VERSION 5.7 ;
  NOWIREEXTENSIONATPIN ON ;
  DIVIDERCHAR "/" ;
  BUSBITCHARS "[]" ;
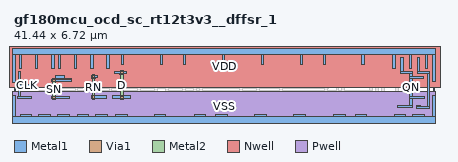
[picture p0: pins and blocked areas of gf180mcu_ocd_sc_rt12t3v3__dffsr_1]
MACRO gf180mcu_ocd_sc_rt12t3v3__dffsr_1
  CLASS CORE ;
  FOREIGN gf180mcu_ocd_sc_rt12t3v3__dffsr_1 ;
  ORIGIN 0.000 0.000 ;
  SIZE 41.440 BY 6.720 ;
  SYMMETRY X Y ;
  SITE unithd ;
  PIN D
    DIRECTION INPUT ;
    USE SIGNAL ;
    ANTENNAGATEAREA 1.672300 ;
    PORT
      LAYER Metal1 ;
        RECT 10.450 4.770 10.830 4.790 ;
        RECT 9.940 4.540 11.080 4.770 ;
        RECT 10.450 4.530 10.830 4.540 ;
        RECT 9.730 2.075 11.490 2.405 ;
      LAYER Via1 ;
        RECT 10.510 4.530 10.770 4.790 ;
        RECT 10.510 2.105 10.770 2.365 ;
      LAYER Metal2 ;
        RECT 10.500 2.045 10.780 4.855 ;
    END
  END D
  PIN CLK
    DIRECTION INPUT ;
    USE SIGNAL ;
    ANTENNAGATEAREA 1.672300 ;
    PORT
      LAYER Metal1 ;
        RECT 0.445 3.525 0.675 4.825 ;
        RECT 0.370 3.195 1.870 3.525 ;
        RECT 0.445 2.320 0.675 3.195 ;
        RECT 0.345 2.090 1.770 2.320 ;
    END
  END CLK
  PIN SN
    DIRECTION INPUT ;
    USE SIGNAL ;
    ANTENNAGATEAREA 1.672300 ;
    PORT
      LAYER Metal1 ;
        RECT 4.060 4.085 4.995 4.385 ;
        RECT 4.060 4.015 5.710 4.085 ;
        RECT 3.725 3.755 5.710 4.015 ;
        RECT 3.730 2.320 4.110 2.335 ;
        RECT 3.730 2.090 5.500 2.320 ;
        RECT 3.730 2.075 4.110 2.090 ;
      LAYER Via1 ;
        RECT 3.790 3.755 4.050 4.015 ;
        RECT 3.790 2.075 4.050 2.335 ;
      LAYER Metal2 ;
        RECT 3.780 2.010 4.060 4.075 ;
    END
  END SN
  PIN RN
    DIRECTION INPUT ;
    USE SIGNAL ;
    ANTENNAGATEAREA 1.672300 ;
    PORT
      LAYER Metal1 ;
        RECT 7.850 4.355 8.195 4.390 ;
        RECT 7.620 4.145 8.195 4.355 ;
        RECT 7.620 4.095 8.030 4.145 ;
        RECT 7.650 2.075 9.165 2.405 ;
      LAYER Via1 ;
        RECT 7.710 4.095 7.970 4.355 ;
        RECT 7.710 2.110 7.970 2.370 ;
      LAYER Metal2 ;
        RECT 7.700 2.020 7.980 4.470 ;
    END
  END RN
  PIN Q
    DIRECTION OUTPUT ;
    USE SIGNAL ;
    ANTENNADIFFAREA 0.976900 ;
    PORT
      LAYER Metal1 ;
        RECT 39.775 4.820 40.005 6.180 ;
        RECT 39.775 4.560 41.010 4.820 ;
        RECT 39.730 1.380 40.110 1.425 ;
        RECT 40.750 1.380 41.010 4.560 ;
        RECT 39.730 1.120 41.010 1.380 ;
    END
  END Q
  PIN QN
    DIRECTION OUTPUT ;
    USE SIGNAL ;
    ANTENNAGATEAREA 1.672300 ;
    ANTENNADIFFAREA 0.976900 ;
    PORT
      LAYER Metal1 ;
        RECT 38.175 4.820 38.405 6.180 ;
        RECT 38.175 4.560 39.330 4.820 ;
        RECT 39.070 4.290 39.330 4.560 ;
        RECT 39.070 4.060 40.420 4.290 ;
        RECT 39.070 2.320 39.330 4.060 ;
        RECT 39.070 2.075 40.490 2.320 ;
        RECT 39.070 1.430 39.330 2.075 ;
        RECT 38.200 1.425 39.330 1.430 ;
        RECT 37.880 1.195 39.330 1.425 ;
    END
  END QN
  PIN VDD
    DIRECTION INOUT ;
    USE POWER ;
    SHAPE ABUTMENT ;
    PORT
      LAYER Nwell ;
        RECT -0.450 3.245 42.210 7.330 ;
      LAYER Metal1 ;
        RECT -0.115 6.420 41.555 7.020 ;
        RECT -0.115 3.745 0.115 6.420 ;
        RECT 0.525 5.060 0.755 6.420 ;
        RECT 2.125 5.060 2.355 6.420 ;
        RECT 3.725 5.065 3.955 6.420 ;
        RECT 4.365 5.060 4.595 6.420 ;
        RECT 5.965 5.060 6.195 6.420 ;
        RECT 7.565 5.060 7.795 6.420 ;
        RECT 9.165 5.065 9.395 6.420 ;
        RECT 10.605 5.520 10.835 6.420 ;
        RECT 14.450 5.520 14.680 6.420 ;
        RECT 16.715 5.520 16.945 6.420 ;
        RECT 20.555 5.520 20.785 6.420 ;
        RECT 24.395 5.520 24.625 6.420 ;
        RECT 28.235 5.520 28.465 6.420 ;
        RECT 30.495 5.520 30.725 6.420 ;
        RECT 34.335 5.520 34.565 6.420 ;
        RECT 37.375 5.060 37.605 6.420 ;
        RECT 38.975 5.060 39.205 6.420 ;
        RECT 40.575 5.065 40.805 6.420 ;
        RECT 41.325 3.750 41.555 6.420 ;
    END
  END VDD
  PIN VSS
    DIRECTION INOUT ;
    USE GROUND ;
    SHAPE ABUTMENT ;
    PORT
      LAYER Pwell ;
        RECT -0.180 -0.180 41.620 2.815 ;
      LAYER Metal1 ;
        RECT -0.115 0.300 0.115 2.410 ;
        RECT 0.600 0.300 1.710 0.585 ;
        RECT 2.450 0.300 3.560 0.585 ;
        RECT 4.340 0.300 5.450 0.585 ;
        RECT 6.220 0.300 7.330 0.585 ;
        RECT 8.070 0.300 9.180 0.585 ;
        RECT 10.060 0.300 11.170 0.585 ;
        RECT 13.855 0.300 14.965 0.585 ;
        RECT 17.770 0.300 18.905 0.585 ;
        RECT 19.930 0.300 21.040 0.585 ;
        RECT 23.770 0.300 24.880 0.585 ;
        RECT 27.605 0.300 28.715 0.585 ;
        RECT 31.550 0.300 32.685 0.585 ;
        RECT 33.710 0.300 34.820 0.585 ;
        RECT 37.500 0.300 38.610 0.585 ;
        RECT 39.350 0.300 40.460 0.585 ;
        RECT 41.325 0.300 41.555 2.410 ;
        RECT -0.115 -0.300 41.555 0.300 ;
    END
  END VSS
  OBS
      LAYER Metal1 ;
        RECT 1.325 4.820 1.555 6.180 ;
        RECT 2.925 4.820 3.155 6.180 ;
        RECT 5.165 4.820 5.395 6.180 ;
        RECT 6.765 4.820 6.995 6.180 ;
        RECT 8.365 4.820 8.595 6.180 ;
        RECT 9.805 5.290 10.035 6.190 ;
        RECT 11.405 5.960 13.235 6.190 ;
        RECT 11.405 5.290 11.635 5.960 ;
        RECT 9.805 5.060 11.635 5.290 ;
        RECT 12.190 4.975 12.450 5.730 ;
        RECT 13.005 5.055 13.235 5.960 ;
        RECT 13.650 5.290 13.880 6.180 ;
        RECT 15.250 5.290 15.480 6.180 ;
        RECT 15.915 5.290 16.145 6.190 ;
        RECT 17.515 5.960 19.345 6.190 ;
        RECT 17.515 5.290 17.745 5.960 ;
        RECT 13.650 5.060 17.745 5.290 ;
        RECT 1.325 4.560 2.695 4.820 ;
        RECT 2.925 4.560 3.490 4.820 ;
        RECT 5.165 4.770 6.350 4.820 ;
        RECT 5.165 4.560 6.535 4.770 ;
        RECT 6.765 4.560 7.470 4.820 ;
        RECT 8.365 4.560 9.710 4.820 ;
        RECT 12.205 4.770 12.450 4.975 ;
        RECT 2.110 4.540 2.695 4.560 ;
        RECT 2.110 2.875 2.370 4.540 ;
        RECT 3.230 3.370 3.490 4.560 ;
        RECT 5.960 4.540 6.535 4.560 ;
        RECT 11.585 4.540 11.975 4.770 ;
        RECT 12.205 4.540 13.545 4.770 ;
        RECT 13.800 4.600 15.835 4.830 ;
        RECT 13.800 4.565 14.190 4.600 ;
        RECT 11.690 4.300 11.920 4.540 ;
        RECT 14.905 4.300 15.340 4.325 ;
        RECT 8.560 4.070 15.340 4.300 ;
        RECT 8.560 3.835 8.790 4.070 ;
        RECT 14.920 4.060 15.340 4.070 ;
        RECT 15.605 4.290 15.835 4.600 ;
        RECT 16.455 4.540 17.010 4.805 ;
        RECT 17.540 4.540 18.085 4.805 ;
        RECT 18.315 4.770 18.610 5.730 ;
        RECT 19.115 5.055 19.345 5.960 ;
        RECT 19.755 5.290 19.985 6.190 ;
        RECT 21.355 5.960 23.185 6.190 ;
        RECT 21.355 5.290 21.585 5.960 ;
        RECT 19.755 5.060 21.585 5.290 ;
        RECT 22.155 5.025 22.530 5.730 ;
        RECT 22.955 5.055 23.185 5.960 ;
        RECT 23.595 5.290 23.825 6.190 ;
        RECT 25.195 5.960 27.025 6.190 ;
        RECT 25.195 5.290 25.425 5.960 ;
        RECT 23.595 5.060 25.425 5.290 ;
        RECT 25.995 5.720 26.235 5.730 ;
        RECT 22.270 5.000 22.530 5.025 ;
        RECT 23.725 4.770 24.295 4.805 ;
        RECT 18.315 4.540 21.205 4.770 ;
        RECT 21.450 4.540 22.400 4.770 ;
        RECT 23.725 4.540 24.715 4.770 ;
        RECT 21.515 4.290 21.745 4.540 ;
        RECT 25.480 4.290 25.710 4.825 ;
        RECT 25.995 4.770 26.450 5.720 ;
        RECT 26.795 5.055 27.025 5.960 ;
        RECT 27.435 5.290 27.665 6.180 ;
        RECT 29.035 5.290 29.265 6.180 ;
        RECT 29.695 5.290 29.925 6.190 ;
        RECT 31.295 5.960 33.125 6.190 ;
        RECT 31.295 5.290 31.525 5.960 ;
        RECT 27.435 5.060 31.525 5.290 ;
        RECT 32.040 5.040 32.610 5.730 ;
        RECT 32.895 5.055 33.125 5.960 ;
        RECT 33.535 5.290 33.765 6.190 ;
        RECT 35.135 5.960 36.965 6.190 ;
        RECT 35.135 5.290 35.365 5.960 ;
        RECT 33.535 5.060 35.365 5.290 ;
        RECT 29.870 4.810 30.945 4.825 ;
        RECT 25.995 4.540 28.330 4.770 ;
        RECT 29.870 4.540 30.990 4.810 ;
        RECT 31.305 4.545 32.110 4.805 ;
        RECT 32.350 4.770 32.610 5.040 ;
        RECT 35.710 4.980 36.165 5.725 ;
        RECT 36.735 5.055 36.965 5.960 ;
        RECT 31.305 4.540 31.865 4.545 ;
        RECT 32.350 4.540 34.315 4.770 ;
        RECT 34.585 4.520 36.530 4.750 ;
        RECT 34.585 4.290 34.815 4.520 ;
        RECT 15.605 4.060 34.815 4.290 ;
        RECT 35.120 4.060 36.060 4.290 ;
        RECT 6.545 3.605 8.790 3.835 ;
        RECT 9.330 3.815 9.710 3.830 ;
        RECT 16.195 3.815 18.060 3.830 ;
        RECT 29.620 3.815 32.115 3.830 ;
        RECT 3.170 3.355 3.550 3.370 ;
        RECT 6.545 3.355 6.775 3.605 ;
        RECT 9.330 3.600 32.115 3.815 ;
        RECT 9.330 3.585 16.415 3.600 ;
        RECT 17.680 3.585 29.840 3.600 ;
        RECT 9.330 3.570 9.710 3.585 ;
        RECT 17.680 3.565 18.060 3.585 ;
        RECT 31.730 3.570 32.115 3.600 ;
        RECT 3.170 3.125 6.775 3.355 ;
        RECT 7.085 3.335 7.470 3.370 ;
        RECT 16.605 3.335 16.985 3.370 ;
        RECT 30.610 3.335 30.990 3.365 ;
        RECT 3.170 3.110 3.550 3.125 ;
        RECT 7.085 3.105 30.990 3.335 ;
        RECT 35.120 2.875 35.350 4.060 ;
        RECT 2.110 2.645 14.190 2.875 ;
        RECT 2.110 2.320 2.370 2.645 ;
        RECT 5.970 2.320 6.350 2.335 ;
        RECT 12.865 2.325 13.110 2.645 ;
        RECT 13.805 2.610 14.190 2.645 ;
        RECT 14.930 2.645 35.350 2.875 ;
        RECT 14.930 2.610 15.310 2.645 ;
        RECT 2.110 2.090 3.495 2.320 ;
        RECT 5.970 2.090 7.345 2.320 ;
        RECT 12.000 2.095 13.110 2.325 ;
        RECT 13.350 2.090 16.125 2.320 ;
        RECT 16.355 2.130 17.205 2.395 ;
        RECT 17.680 2.380 18.060 2.395 ;
        RECT 22.210 2.385 22.590 2.415 ;
        RECT 17.680 2.150 18.820 2.380 ;
        RECT 19.060 2.150 22.590 2.385 ;
        RECT 22.895 2.375 23.170 2.645 ;
        RECT 17.680 2.130 18.060 2.150 ;
        RECT 2.110 1.425 2.370 2.090 ;
        RECT 5.970 2.075 6.350 2.090 ;
        RECT 3.170 1.425 3.550 1.440 ;
        RECT 5.970 1.425 6.350 1.440 ;
        RECT 7.090 1.425 7.470 1.440 ;
        RECT 9.330 1.430 9.715 1.440 ;
        RECT 8.745 1.425 9.715 1.430 ;
        RECT 11.610 1.425 11.840 1.815 ;
        RECT 0.980 1.195 2.370 1.425 ;
        RECT 2.830 1.195 3.550 1.425 ;
        RECT 4.720 1.195 6.350 1.425 ;
        RECT 6.600 1.195 7.470 1.425 ;
        RECT 8.450 1.195 9.715 1.425 ;
        RECT 10.440 1.195 11.840 1.425 ;
        RECT 3.170 1.180 3.550 1.195 ;
        RECT 5.970 1.180 6.350 1.195 ;
        RECT 7.090 1.180 7.470 1.195 ;
        RECT 9.330 1.180 9.715 1.195 ;
        RECT 11.610 0.770 11.840 1.195 ;
        RECT 12.190 1.440 12.450 1.540 ;
        RECT 13.350 1.440 13.610 2.090 ;
        RECT 15.895 1.885 16.125 2.090 ;
        RECT 19.060 1.885 19.290 2.150 ;
        RECT 22.830 2.145 23.260 2.375 ;
        RECT 25.775 2.325 26.010 2.645 ;
        RECT 23.820 2.090 25.055 2.320 ;
        RECT 25.685 2.095 26.620 2.325 ;
        RECT 26.860 2.090 29.885 2.320 ;
        RECT 30.125 2.140 31.100 2.400 ;
        RECT 31.460 2.380 32.110 2.390 ;
        RECT 31.460 2.150 32.605 2.380 ;
        RECT 35.650 2.345 36.065 2.375 ;
        RECT 31.460 2.130 32.110 2.150 ;
        RECT 23.820 1.995 24.210 2.090 ;
        RECT 23.820 1.915 24.140 1.995 ;
        RECT 12.190 1.180 13.610 1.440 ;
        RECT 15.430 1.425 15.660 1.820 ;
        RECT 15.895 1.655 19.290 1.885 ;
        RECT 19.520 1.685 24.140 1.915 ;
        RECT 19.520 1.425 19.750 1.685 ;
        RECT 21.480 1.425 21.710 1.455 ;
        RECT 14.235 1.195 15.660 1.425 ;
        RECT 16.180 1.195 19.750 1.425 ;
        RECT 20.310 1.195 21.710 1.425 ;
        RECT 12.190 0.720 12.450 1.180 ;
        RECT 15.430 0.750 15.660 1.195 ;
        RECT 18.290 0.815 18.670 1.195 ;
        RECT 19.520 0.770 19.750 1.195 ;
        RECT 21.480 0.770 21.710 1.195 ;
        RECT 22.210 0.770 22.605 1.455 ;
        RECT 25.320 1.425 25.550 1.815 ;
        RECT 26.190 1.560 26.450 1.620 ;
        RECT 26.190 1.480 26.465 1.560 ;
        RECT 24.150 1.195 25.550 1.425 ;
        RECT 25.320 0.770 25.550 1.195 ;
        RECT 26.160 1.425 26.465 1.480 ;
        RECT 26.860 1.425 27.120 2.090 ;
        RECT 29.655 1.885 29.885 2.090 ;
        RECT 32.840 2.115 36.065 2.345 ;
        RECT 36.300 2.350 36.530 4.520 ;
        RECT 37.610 4.060 38.820 4.290 ;
        RECT 36.300 2.120 37.135 2.350 ;
        RECT 37.665 2.320 37.895 4.060 ;
        RECT 32.840 1.885 33.070 2.115 ;
        RECT 37.665 2.090 38.810 2.320 ;
        RECT 37.665 1.885 37.915 2.090 ;
        RECT 29.180 1.425 29.410 1.825 ;
        RECT 29.655 1.655 33.070 1.885 ;
        RECT 33.300 1.655 37.915 1.885 ;
        RECT 33.300 1.425 33.530 1.655 ;
        RECT 26.160 1.195 27.120 1.425 ;
        RECT 27.985 1.195 29.410 1.425 ;
        RECT 29.930 1.195 33.530 1.425 ;
        RECT 34.090 1.195 35.480 1.425 ;
        RECT 26.160 1.140 26.465 1.195 ;
        RECT 26.190 1.010 26.465 1.140 ;
        RECT 26.190 0.950 26.450 1.010 ;
        RECT 29.180 0.750 29.410 1.195 ;
        RECT 32.290 0.815 32.670 1.195 ;
        RECT 33.300 0.980 33.530 1.195 ;
        RECT 35.250 0.740 35.480 1.195 ;
        RECT 35.710 1.165 36.405 1.395 ;
        RECT 35.710 0.755 36.035 1.165 ;
      LAYER Via1 ;
        RECT 12.190 5.035 12.450 5.645 ;
        RECT 18.350 5.055 18.610 5.665 ;
        RECT 22.270 5.065 22.530 5.670 ;
        RECT 6.030 4.550 6.290 4.815 ;
        RECT 7.150 4.560 7.410 4.820 ;
        RECT 9.390 4.560 9.650 4.820 ;
        RECT 13.870 4.565 14.130 4.830 ;
        RECT 14.990 4.060 15.250 4.325 ;
        RECT 16.665 4.540 16.925 4.805 ;
        RECT 17.740 4.540 18.000 4.805 ;
        RECT 26.190 5.050 26.450 5.660 ;
        RECT 23.950 4.540 24.210 4.805 ;
        RECT 32.350 4.945 32.610 5.670 ;
        RECT 35.710 5.040 35.970 5.665 ;
        RECT 30.670 4.550 30.930 4.810 ;
        RECT 31.790 4.545 32.050 4.805 ;
        RECT 3.230 3.110 3.490 3.370 ;
        RECT 9.390 3.570 9.650 3.830 ;
        RECT 17.740 3.565 18.000 3.830 ;
        RECT 31.790 3.570 32.050 3.830 ;
        RECT 7.150 3.105 7.410 3.365 ;
        RECT 16.665 3.105 16.925 3.370 ;
        RECT 30.670 3.105 30.930 3.365 ;
        RECT 6.030 2.075 6.290 2.335 ;
        RECT 13.870 2.610 14.130 2.875 ;
        RECT 14.990 2.610 15.250 2.875 ;
        RECT 16.665 2.130 16.925 2.395 ;
        RECT 17.740 2.130 18.000 2.395 ;
        RECT 22.270 2.150 22.530 2.415 ;
        RECT 3.230 1.180 3.490 1.440 ;
        RECT 6.030 1.180 6.290 1.440 ;
        RECT 7.150 1.180 7.410 1.440 ;
        RECT 9.390 1.180 9.650 1.440 ;
        RECT 12.190 0.785 12.450 1.475 ;
        RECT 23.950 2.055 24.210 2.320 ;
        RECT 30.670 2.140 30.930 2.400 ;
        RECT 31.790 2.130 32.050 2.390 ;
        RECT 18.350 0.815 18.610 1.415 ;
        RECT 22.270 0.770 22.545 1.455 ;
        RECT 35.710 2.115 35.970 2.375 ;
        RECT 32.350 0.815 32.610 1.415 ;
        RECT 35.710 0.815 35.970 1.335 ;
      LAYER Metal2 ;
        RECT 3.220 1.120 3.500 3.430 ;
        RECT 6.020 1.115 6.300 4.875 ;
        RECT 7.140 1.115 7.420 4.880 ;
        RECT 9.380 1.115 9.660 4.890 ;
        RECT 12.180 0.720 12.460 5.705 ;
        RECT 13.860 2.545 14.140 4.890 ;
        RECT 14.980 2.545 15.260 4.390 ;
        RECT 16.655 2.070 16.935 4.865 ;
        RECT 17.730 2.065 18.010 4.870 ;
        RECT 18.340 0.745 18.620 5.730 ;
        RECT 22.260 1.955 22.540 5.735 ;
        RECT 23.940 1.995 24.220 4.880 ;
        RECT 22.260 0.700 22.555 1.955 ;
        RECT 26.180 0.950 26.460 5.720 ;
        RECT 30.660 2.070 30.940 4.880 ;
        RECT 31.780 2.055 32.060 4.865 ;
        RECT 32.340 1.005 32.620 5.740 ;
        RECT 32.335 0.700 32.620 1.005 ;
        RECT 35.700 0.755 35.980 5.770 ;
  END
END gf180mcu_ocd_sc_rt12t3v3__dffsr_1
END LIBRARY

